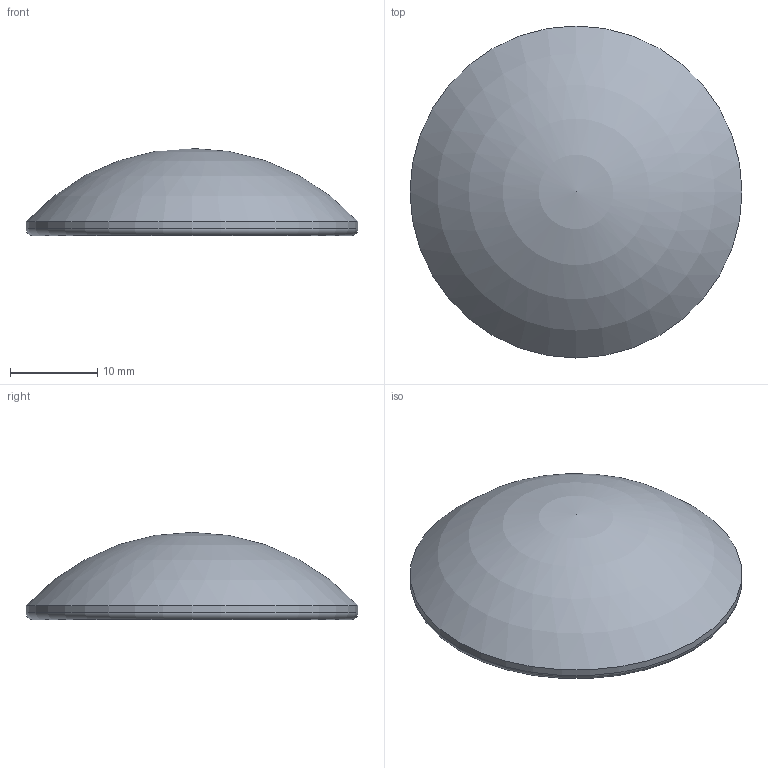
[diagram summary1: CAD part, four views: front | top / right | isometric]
STEP (ISO 10303-21) file: header records copied from the file, then geometry measured from it (millimetres).
FILE_DESCRIPTION(('Open CASCADE Model'),'2;1');
FILE_NAME('Open CASCADE Shape Model','2026-11-10T21:02:45',('Author'),( 'Open CASCADE'),'Open CASCADE STEP processor 7.9','Open CASCADE 7.9' ,'Unknown');
FILE_SCHEMA(('AUTOMOTIVE_DESIGN { 1 0 10303 214 1 1 1 1 }'));
Length unit declared in the file: millimetre
Products named in the file (1): Open CASCADE STEP translator 7.9 5
Bounding box: 38.1 x 38.1 x 10 mm (x, y, z)
Volume: 4035.4 mm3; surface area: 3499.2 mm2
Topology: 1 solids, 1 shells, 10 faces, 17 edges, 10 vertices
Faces by surface type: cylinder 4, plane 3, sphere 2, torus 1
Full cylindrical faces by diameter (mm): 8 x1, 12 x1, 25 x1, 38.1 x1
Entity records: 454 total; most frequent: DIRECTION 82, CARTESIAN_POINT 69, ORIENTED_EDGE 32, PCURVE 32, DEFINITIONAL_REPRESENTATION 32, LINE 31, VECTOR 31, AXIS2_PLACEMENT_3D 23
